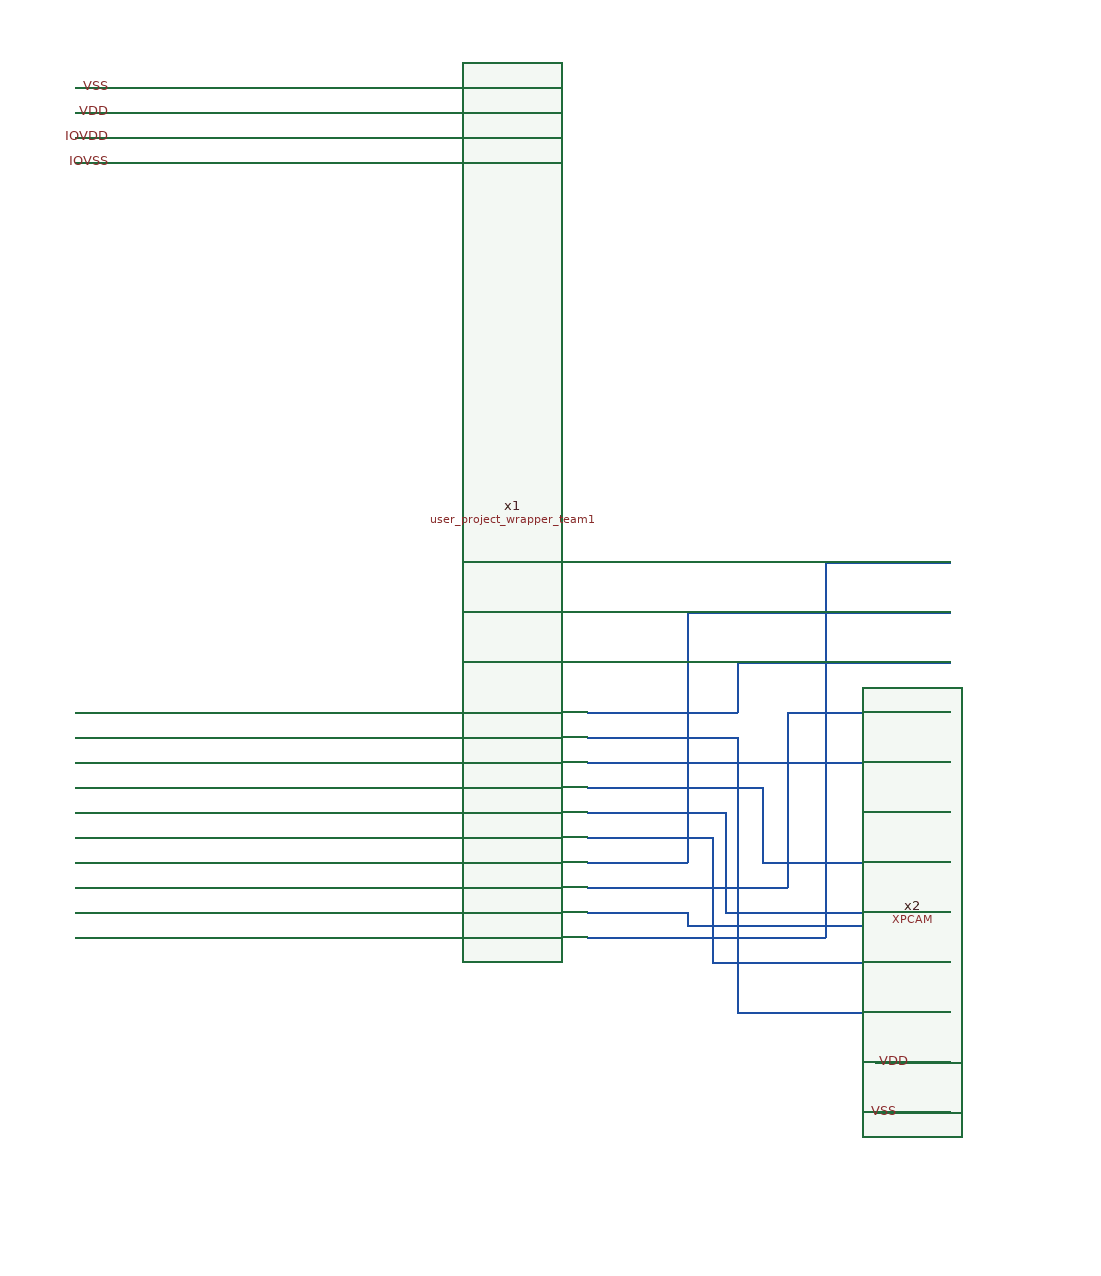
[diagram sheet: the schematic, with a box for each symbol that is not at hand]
v {xschem version=3.4.6 file_version=1.2}
G {}
K {}
V {}
S {}
E {}
N 1400 -980 1520 -980 {lab=#net1}
N 1520 -1020 1520 -980 {lab=#net1}
N 1520 -1020 1690 -1020 {lab=#net1}
N 1400 -960 1520 -960 {lab=#net2}
N 1520 -960 1520 -740 {lab=#net2}
N 1520 -740 1690 -740 {lab=#net2}
N 1400 -940 1690 -940 {lab=#net3}
N 1400 -920 1540 -920 {lab=#net4}
N 1540 -920 1540 -860 {lab=#net4}
N 1540 -860 1690 -860 {lab=#net4}
N 1400 -900 1510 -900 {lab=#net5}
N 1510 -900 1510 -820 {lab=#net5}
N 1510 -820 1690 -820 {lab=#net5}
N 1400 -880 1500 -880 {lab=#net6}
N 1500 -880 1500 -780 {lab=#net6}
N 1500 -780 1690 -780 {lab=#net6}
N 1480 -1060 1690 -1060 {lab=#net7}
N 1480 -1060 1480 -860 {lab=#net7}
N 1400 -860 1480 -860 {lab=#net7}
N 1400 -840 1560 -840 {lab=#net8}
N 1560 -980 1560 -840 {lab=#net8}
N 1560 -980 1690 -980 {lab=#net8}
N 1400 -820 1480 -820 {lab=#net9}
N 1480 -820 1480 -810 {lab=#net9}
N 1480 -810 1670 -810 {lab=#net9}
N 1670 -900 1670 -810 {lab=#net9}
N 1670 -900 1690 -900 {lab=#net9}
N 1400 -800 1590 -800 {lab=#net10}
N 1590 -1100 1590 -800 {lab=#net10}
N 1590 -1100 1690 -1100 {lab=#net10}
N 1630 -700 1690 -700 {lab=VDD}
N 1630 -660 1690 -660 {lab=VSS}
N 990 -980 1040 -980 {lab=#net11}
N 990 -960 1040 -960 {lab=#net12}
N 990 -940 1040 -940 {lab=#net13}
N 990 -920 1040 -920 {lab=#net14}
N 990 -900 1040 -900 {lab=#net15}
N 990 -880 1040 -880 {lab=#net16}
N 990 -860 1040 -860 {lab=#net17}
N 990 -840 1040 -840 {lab=#net18}
N 990 -820 1040 -820 {lab=#net19}
N 990 -800 1040 -800 {lab=#net20}
N 990 -1480 1040 -1480 {lab=VSS}
N 990 -1460 1040 -1460 {lab=VDD}
N 990 -1440 1040 -1440 {lab=IOVDD}
N 990 -1420 1040 -1420 {lab=vss}
C {user_project_wrapper_team1.sym} 1280 -1060 0 0 {name=x1}
C {XPCAM.sym} 1660 -600 0 0 {name=x2}
C {lab_wire.sym} 1650 -660 0 0 {name=p1 sig_type=std_logic lab=VSS
}
C {lab_wire.sym} 1660 -700 0 0 {name=p2 sig_type=std_logic lab=VDD
}
C {lab_wire.sym} 1020 -1480 0 0 {name=p3 sig_type=std_logic lab=VSS}
C {lab_wire.sym} 1020 -1460 0 0 {name=p4 sig_type=std_logic lab=VDD}
C {lab_wire.sym} 1020 -1440 0 0 {name=p5 sig_type=std_logic lab=IOVDD}
C {lab_wire.sym} 1020 -1420 0 0 {name=p6 sig_type=std_logic lab=IOVSS}
